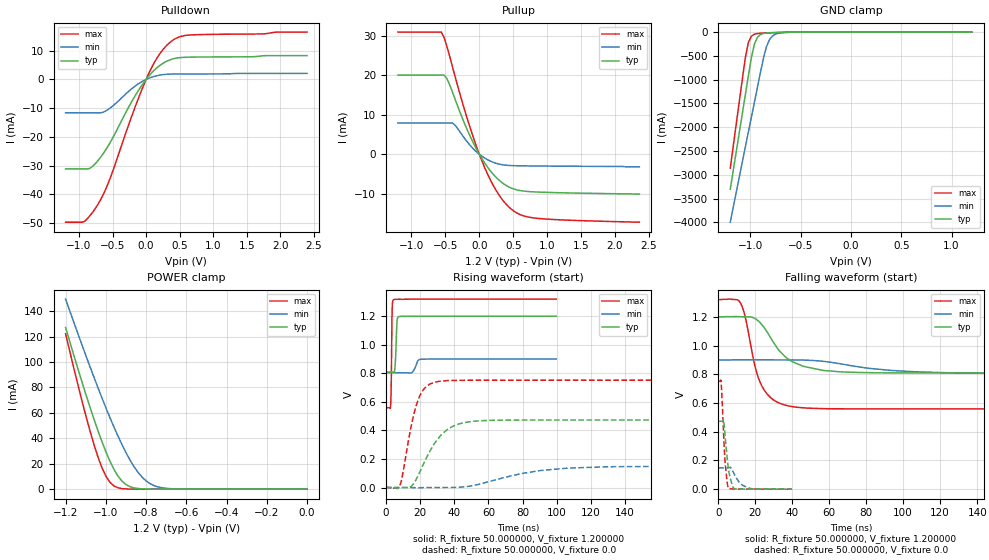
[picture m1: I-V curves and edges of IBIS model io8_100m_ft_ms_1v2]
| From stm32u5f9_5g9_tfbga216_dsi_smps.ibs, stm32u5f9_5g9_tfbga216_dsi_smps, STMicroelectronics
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|   Model io8_100m_ft_ms_1v2
[Model]  io8_100m_ft_ms_1v2
Model_type I/O
Polarity   Non-Inverting
Enable   Active-Low
Vinl =   0.360000V
Vinh =   0.840000V
Vmeas =  0.600000V
Cref =   50.000000pF
Rref =   100.000000M
Vref =   0.0V
C_comp   2.947800pF   2.877700pF   2.996100pF
[Temperature Range]   25.000000   0.140000k   -40.000000
[Pullup Reference]   1.200000V   0.900000V   1.320000V
[Pulldown Reference]   0.0V   0.0V   0.0V
[POWER Clamp Reference]   1.200000V   0.900000V   1.320000V
[GND Clamp Reference]   0.0V   0.0V   0.0V
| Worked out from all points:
|   slope of the pulldown table from 0 to 0.18 V, typ, clamps not added: 40.7 ohm
|   slope of the pullup table from 0 to 0.18 V, typ, clamps not added: 39.5 ohm
|   GND clamp passes 1 mA (typ) near -0.51 V on its own axis
|   POWER clamp passes 1 mA (typ) near -0.86 V on its own axis
|   rising waveform, R_fixture 50.000000, V_fixture 1.200000: 20-80 % time 749ps typ, 2.05ns min, 441ps max; typ from 0.809 V to 1.2 V
|   rising waveform, R_fixture 50.000000, V_fixture 0.0: 20-80 % time 14ns typ, 33.6ns min, 7.83ns max; typ from 0 V to 0.473 V
|   falling waveform, R_fixture 50.000000, V_fixture 1.200000: 20-80 % time 15.1ns typ, 36.8ns min, 8.74ns max; typ from 1.2 V to 0.809 V
|   falling waveform, R_fixture 50.000000, V_fixture 0.0: 20-80 % time 2.5ns typ, 4.76ns min, 1.84ns max; typ from 0.473 V to 0 V
[Pulldown]
|Voltage   I(typ)   I(min)   I(max)
-1.2V     -31.16mA   -11.61mA   -49.71mA
-920mV    -31.16mA   -11.61mA   -49.48mA
-840mV    -31mA      -11.61mA   -47.54mA
-720mV    -28.32mA   -11.61mA   -43.58mA
-560mV    -22.95mA   -10.37mA   -35.89mA
-200mV    -7.146mA   -2.964mA   -11.89mA
0V        0A         0A         0A
160mV     4.047mA    1.298mA    7.361mA
360mV     6.87mA     1.87mA     13mA
480mV     7.543mA    1.91mA     14.69mA
640mV     7.764mA    1.923mA    15.46mA
2.4V      8.308mA    2.101mA    16.5mA
[Pullup]
|Voltage   I(typ)   I(min)   I(max)
-1.2V     20.06mA    7.936mA    30.97mA
-560mV    20.06mA    7.936mA    30.97mA
-480mV    19.26mA    7.936mA    27.49mA
-360mV    14.08mA    7.421mA    19.88mA
-160mV    5.494mA    2.768mA    8.045mA
40mV      -1.16mA    -508.1uA   -1.774mA
240mV     -5.73mA    -2.256mA   -8.953mA
360mV     -7.518mA   -2.716mA   -11.96mA
480mV     -8.639mA   -2.877mA   -14.04mA
640mV     -9.31mA    -2.942mA   -15.55mA
880mV     -9.601mA   -2.986mA   -16.29mA
2.36V     -10.1mA    -3.2mA     -17.23mA
[GND_clamp]
|Voltage   I(typ)   I(min)   I(max)
-1.2V     -3.305A    -3.998A    -2.862A
-1.05V    -1.316A    -2.418A    -539.3mA
-1.02V    -921mA     -2.103A    -218.8mA
-990mV    -539.5mA   -1.788A    -87.43mA
-960mV    -252.1mA   -1.474A    -44.36mA
-930mV    -110.5mA   -1.16A     -30.32mA
-870mV    -28.03mA   -549.1mA   -21.09mA
-840mV    -18.43mA   -305.6mA   -18.27mA
-810mV    -13.9mA    -159.7mA   -15.73mA
-780mV    -11.23mA   -82.35mA   -13.37mA
-600mV    -2.976mA   -4.272mA   -3.058mA
1.2V      0A         14.74nA    0A
[POWER_clamp]
|Voltage   I(typ)   I(min)   I(max)
-1.2V     127mA      149.4mA    122.2mA
-1.12V    84.97mA    114mA      70.27mA
-1.06V    55.51mA    88.42mA    35.67mA
-1.02V    37.63mA    72.04mA    17.17mA
-1V       29.51mA    64.13mA    10.3mA
-960mV    15.69mA    48.99mA    2.571mA
-900mV    3.624mA    28.77mA    182.8uA
-840mV    490.7uA    13.24mA    11.35uA
-800mV    116.8uA    6.532mA    1.77uA
-740mV    13.2uA     1.723mA    109.1nA
-620mV    167.3nA    79.35uA    0A
0V        0A         17.84nA    0A
[Ramp]
| variable   typ   min   max
dV/dt_r  0.28373/13.95894n   88.89587m/33.56367n 0.45095/7.81701n
dV/dt_f  0.23464/15.11036n   57.88200m/36.76440n 0.45667/8.72831n
R_load = 50.000000
[Rising Waveform]
R_fixture= 50.000000
V_fixture= 1.200000
V_fixture_min= 0.900000
V_fixture_max= 1.320000
|time   V(typ)   V(min)   V(max)
0s        809mV      803.5mV    558.9mV
2.803ns   809mV      803.5mV    575.1mV
3.203ns   809.1mV    803.5mV    763.8mV
3.604ns   809mV      803.5mV    1.211V
4.605ns   804.7mV    803.5mV    1.316V
5.405ns   852.1mV    803.5mV    1.318V
6.607ns   1.173V     803.5mV    1.318V
7.608ns   1.197V     803.5mV    1.319V
20.62ns   1.199V     898.4mV    1.32V
99.7ns    1.2V       900mV      1.32V
[Rising Waveform]
R_fixture= 50.000000
V_fixture= 0.0
V_fixture_min= 0.0
V_fixture_max= 0.0
|time   V(typ)   V(min)   V(max)
0s        2.143uV    1.134uV    2.528uV
7.808ns   -1.504mV   305.6nV    5.314mV
14.41ns   4.444mV    -158.6uV   405.8mV
18.62ns   77.49mV    -1.841mV   605.4mV
23.42ns   199.9mV    -199.4uV   704.4mV
30.63ns   342.8mV    -16.77uV   742.6mV
39.64ns   431.6mV    522.9uV    750.2mV
57.66ns   468.9mV    32.7mV     751.5mV
106.9ns   472.8mV    136.2mV    751.6mV
299.1ns   472.9mV    148.2mV    751.6mV
[Falling Waveform]
R_fixture= 50.000000
V_fixture= 1.200000
V_fixture_min= 0.900000
V_fixture_max= 1.320000
|time   V(typ)   V(min)   V(max)
0s        1.2V       900mV      1.32V
12.01ns   1.201V     900.6mV    1.297V
14.41ns   1.2V       900.5mV    1.21V
20.02ns   1.187V     900.5mV    849.1mV
23.22ns   1.151V     900.5mV    727.8mV
30.43ns   1.011V     900.2mV    617mV
40.84ns   883.5mV    899.9mV    573.3mV
65.67ns   817.3mV    873.9mV    559.6mV
123.3ns   809mV      810.9mV    558.9mV
398.8ns   809mV      803.5mV    558.9mV
[Falling Waveform]
R_fixture= 50.000000
V_fixture= 0.0
V_fixture_min= 0.0
V_fixture_max= 0.0
|time   V(typ)   V(min)   V(max)
0s        472.9mV    148.2mV    751.6mV
1.522ns   472.9mV    148.2mV    755.6mV
2.883ns   479mV      148.3mV    395.5mV
3.604ns   393.1mV    148.3mV    211.8mV
4.645ns   246.5mV    148.1mV    71.2mV
5.445ns   150.6mV    148.4mV    9.118mV
7.367ns   36.29mV    138.3mV    1.711mV
8.729ns   2.867mV    103.8mV    1.121mV
16.5ns    365.8uV    8.357mV    337.1uV
39.88ns   2.143uV    1.134uV    2.528uV
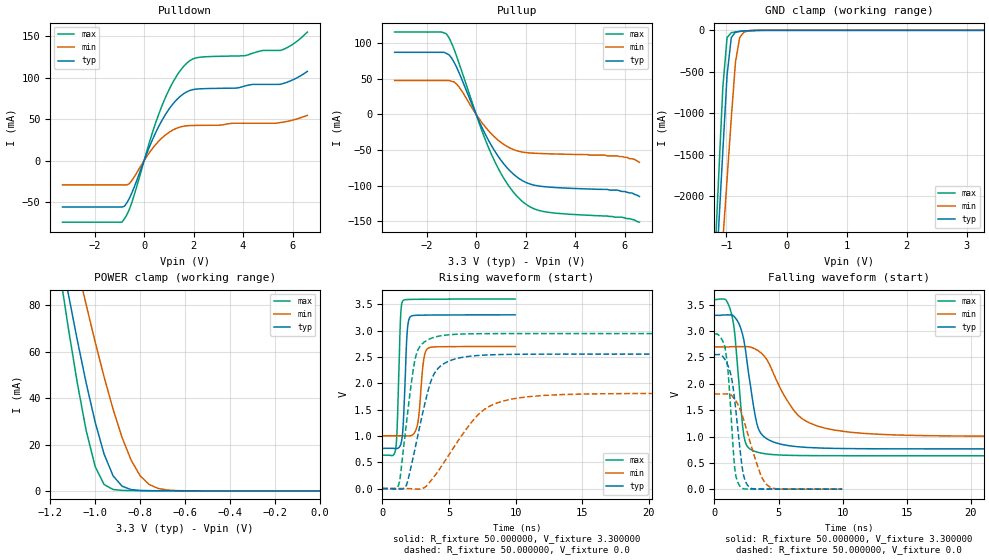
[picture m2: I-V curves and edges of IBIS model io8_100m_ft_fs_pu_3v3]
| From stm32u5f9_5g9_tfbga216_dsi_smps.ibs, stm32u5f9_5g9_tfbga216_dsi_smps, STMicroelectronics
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|   Model io8_100m_ft_fs_pu_3v3
[Model]  io8_100m_ft_fs_pu_3v3
Model_type I/O
Polarity   Non-Inverting
Enable   Active-Low
Vinl =   0.990000V
Vinh =   2.310000V
Vmeas =  1.650000V
Cref =   50.000000pF
Rref =   100.000000M
Vref =   0.0V
C_comp   3.313100pF   3.281800pF   3.354500pF
[Temperature Range]   25.000000   0.140000k   -40.000000
[Pullup Reference]   3.300000V   2.700000V   3.600000V
[Pulldown Reference]   0.0V   0.0V   0.0V
[POWER Clamp Reference]   3.300000V   2.700000V   3.600000V
[GND Clamp Reference]   0.0V   0.0V   0.0V
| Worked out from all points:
|   slope of the pulldown table from 0 to 0.495 V, typ, clamps not added: 14 ohm
|   slope of the pullup table from 0 to 0.495 V, typ, clamps not added: 13.7 ohm
|   GND clamp passes 1 mA (typ) near -0.51 V on its own axis
|   POWER clamp passes 1 mA (typ) near -0.85 V on its own axis
|   rising waveform, R_fixture 50.000000, V_fixture 3.300000: 20-80 % time 244ps typ, 341ps min, 207ps max; typ from 0.765 V to 3.3 V
|   rising waveform, R_fixture 50.000000, V_fixture 0.0: 20-80 % time 1.41ns typ, 3.11ns min, 872ps max; typ from 0.001 V to 2.55 V
|   falling waveform, R_fixture 50.000000, V_fixture 3.300000: 20-80 % time 962ps typ, 2.52ns min, 631ps max; typ from 3.3 V to 0.765 V
|   falling waveform, R_fixture 50.000000, V_fixture 0.0: 20-80 % time 726ps typ, 1.36ns min, 504ps max; typ from 2.55 V to 0.001 V
[Pulldown]
|Voltage   I(typ)   I(min)   I(max)
-3.3V     -56.06mA   -29.42mA   -74.35mA
-900mV    -56.06mA   -29.42mA   -74.35mA
-700mV    -51.09mA   -29.42mA   -65.48mA
-500mV    -39.32mA   -24.2mA    -50.88mA
300mV     22.62mA    13.13mA    30.42mA
800mV     52.54mA    29.36mA    71.75mA
1.3V      72.91mA    38.82mA    101.4mA
1.8V      84.02mA    42.13mA    119.4mA
2.3V      86.61mA    42.5mA     124.8mA
5.5V      91.97mA    45.76mA    132.8mA
6V        97.2mA     48.8mA     140mA
6.6V      107.6mA    54.5mA     155mA
[Pullup]
|Voltage   I(typ)   I(min)   I(max)
-3.3V     87.15mA    47.7mA     115.5mA
-1.2V     85.45mA    47.7mA     112.8mA
-1V       79.36mA    46.62mA    100.4mA
-700mV    59.07mA    38.77mA    72.39mA
200mV     -15.65mA   -9.933mA   -19.95mA
700mV     -48.51mA   -30.11mA   -62.22mA
1.3V      -76.68mA   -45.83mA   -99.4mA
1.9V      -93.37mA   -52.9mA    -122.9mA
2.3V      -98.71mA   -54.23mA   -131.6mA
2.8V      -101.3mA   -54.97mA   -136.5mA
5.7V      -106mA     -58mA      -144mA
6.6V      -115mA     -67mA      -151mA
[GND_clamp]
|Voltage   I(typ)   I(min)   I(max)
-3.3V     -9.848A    -9.957A    -9.458A
-1.2V     -3.312A    -4.013A    -2.863A
-1.13V    -2.381A    -3.274A    -1.769A
-1.06V    -1.452A    -2.535A    -684.7mA
-990mV    -542.9mA   -1.798A    -88.02mA
-920mV    -87.11mA   -1.064A    -28.44mA
-850mV    -22.1mA    -382.4mA   -19.61mA
-780mV    -11.97mA   -86.98mA   -13.71mA
-710mV    -7.619mA   -22.26mA   -8.745mA
-640mV    -4.493mA   -7.773mA   -4.817mA
-360mV    -31.22uA   -172.6uA   -8.607uA
3.28V     0A         15.66nA    -5.841nA
[POWER_clamp]
|Voltage   I(typ)   I(min)   I(max)
-3.28V    1.355A     1.167A     1.665A
-1.16V    105.8mA    131.6mA    95.87mA
-1.12V    85.08mA    114mA      70.45mA
-1.08V    65.19mA    96.88mA    46.75mA
-1.04V    46.48mA    80.2mA     25.96mA
-1V       29.64mA    64.18mA    10.49mA
-960mV    15.81mA    49.06mA    2.743mA
-920mV    6.481mA    35.16mA    612.9uA
-840mV    578.2uA    13.29mA    138.5uA
-760mV    94.37uA    2.807mA    98.56uA
-640mV    40.55uA    159.2uA    59.96uA
0V        0A         19.29nA    0A
[Ramp]
| variable   typ   min   max
dV/dt_r  1.53214/1.41049n   1.08405/3.10150n   1.76624/0.87017n
dV/dt_f  1.52095/0.95861n   1.01838/2.51496n   1.77908/0.62510n
R_load = 50.000000
[Rising Waveform]
R_fixture= 50.000000
V_fixture= 3.300000
V_fixture_min= 2.700000
V_fixture_max= 3.600000
|time   V(typ)   V(min)   V(max)
0s        765.1mV    1.003V     634.9mV
1.021ns   760.9mV    1.003V     795.6mV
1.361ns   828mV      1.003V     3.225V
1.542ns   1.123V     1.002V     3.567V
1.842ns   2.89V      1V         3.591V
2.102ns   3.266V     1.003V     3.593V
2.663ns   3.293V     1.25V      3.596V
3.063ns   3.295V     2.372V     3.597V
3.363ns   3.296V     2.653V     3.597V
9.97ns    3.3V       2.7V       3.6V
[Rising Waveform]
R_fixture= 50.000000
V_fixture= 0.0
V_fixture_min= 0.0
V_fixture_max= 0.0
|time   V(typ)   V(min)   V(max)
0s        834.3uV    854uV      878uV
1.201ns   -6.187mV   859.8uV    56.02mV
1.802ns   61.56mV    847.4uV    1.231V
2.302ns   584mV      -5.222mV   2.233V
2.603ns   935mV      -9.197mV   2.593V
3.504ns   1.924V     106.7mV    2.838V
4.104ns   2.26V      303mV      2.888V
7.307ns   2.531V     1.431V     2.942V
10.41ns   2.551V     1.728V     2.944V
49.85ns   2.554V     1.808V     2.944V
[Falling Waveform]
R_fixture= 50.000000
V_fixture= 3.300000
V_fixture_min= 2.700000
V_fixture_max= 3.600000
|time   V(typ)   V(min)   V(max)
0s        3.3V       2.7V       3.6V
1.301ns   3.307V     2.704V     3.356V
1.602ns   3.26V      2.706V     2.918V
2.002ns   3.088V     2.706V     1.742V
2.402ns   2.676V     2.706V     899.2mV
3.103ns   1.5V       2.67V      723.1mV
3.504ns   1.109V     2.614V     693.6mV
6.507ns   806.1mV    1.409V     640mV
9.51ns    774.3mV    1.117V     635.7mV
49.85ns   765.1mV    1.003V     634.9mV
[Falling Waveform]
R_fixture= 50.000000
V_fixture= 0.0
V_fixture_min= 0.0
V_fixture_max= 0.0
|time   V(typ)   V(min)   V(max)
0s        2.554V     1.808V     2.944V
860.9ps   2.444V     1.808V     2.631V
1.101ns   2.316V     1.811V     2.114V
1.582ns   1.687V     1.707V     407.7mV
2.022ns   699.6mV    1.505V     47.01mV
2.282ns   258.1mV    1.317V     8.261mV
2.583ns   76.46mV    1.065V     3.648mV
3.564ns   3.141mV    304.1mV    2.036mV
4.204ns   2.271mV    61.7mV     1.751mV
9.97ns    834.3uV    854uV      878uV
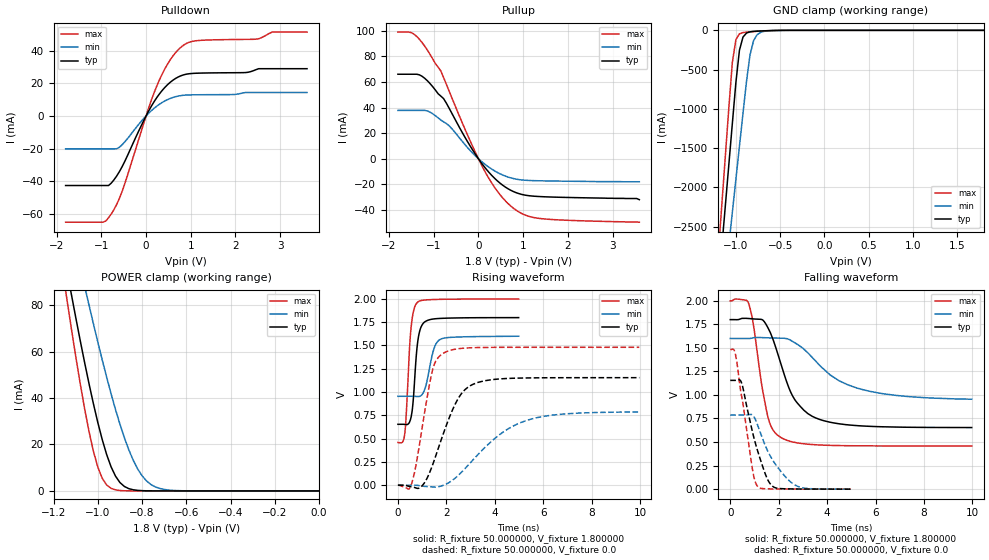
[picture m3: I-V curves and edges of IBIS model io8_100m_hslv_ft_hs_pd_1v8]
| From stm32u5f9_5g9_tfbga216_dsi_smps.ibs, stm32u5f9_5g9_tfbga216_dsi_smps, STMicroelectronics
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|   Model io8_100m_hslv_ft_hs_pd_1v8
[Model]  io8_100m_hslv_ft_hs_pd_1v8
Model_type I/O
Polarity   Non-Inverting
Enable   Active-Low
Vinl =   0.540000V
Vinh =   1.260000V
Vmeas =  0.900000V
Cref =   50.000000pF
Rref =   100.000000M
Vref =   0.0V
C_comp   3.235100pF   3.233200pF   3.282800pF
[Temperature Range]   25.000000   0.140000k   -40.000000
[Pullup Reference]   1.800000V   1.600000V   2.000000V
[Pulldown Reference]   0.0V   0.0V   0.0V
[POWER Clamp Reference]   1.800000V   1.600000V   2.000000V
[GND Clamp Reference]   0.0V   0.0V   0.0V
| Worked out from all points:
|   slope of the pulldown table from 0 to 0.27 V, typ, clamps not added: 21.7 ohm
|   slope of the pullup table from 0 to 0.27 V, typ, clamps not added: 22.6 ohm
|   GND clamp passes 1 mA (typ) near -0.51 V on its own axis
|   POWER clamp passes 1 mA (typ) near -0.86 V on its own axis
|   rising waveform, R_fixture 50.000000, V_fixture 1.800000: 20-80 % time 212ps typ, 327ps min, 198ps max; typ from 0.654 V to 1.8 V
|   rising waveform, R_fixture 50.000000, V_fixture 0.0: 20-80 % time 1.02ns typ, 2.02ns min, 582ps max; typ from 0 V to 1.15 V
|   falling waveform, R_fixture 50.000000, V_fixture 1.800000: 20-80 % time 1.08ns typ, 2.01ns min, 567ps max; typ from 1.8 V to 0.654 V
|   falling waveform, R_fixture 50.000000, V_fixture 0.0: 20-80 % time 708ps typ, 988ps min, 509ps max; typ from 1.15 V to 0 V
[Pulldown]
|Voltage   I(typ)   I(min)   I(max)
-1.8V     -42.74mA   -20.21mA   -65.25mA
-960mV    -42.74mA   -20.21mA   -65.25mA
-780mV    -41.3mA    -20.21mA   -60.25mA
-540mV    -31.39mA   -17.82mA   -46.65mA
0V        0A         -500fA     0A
240mV     11.28mA    6.002mA    18.38mA
480mV     19.17mA    10.02mA    31.83mA
780mV     24.67mA    12.5mA     42.21mA
1.14V     26.24mA    12.99mA    46.23mA
2.46V     28.42mA    14.39mA    47.14mA
2.82V     29mA       14.39mA    51.49mA
3.6V      29mA       14.39mA    51.49mA
[Pullup]
|Voltage   I(typ)   I(min)   I(max)
-1.8V     66.02mA    37.77mA    98.95mA
-1.44V    66.02mA    37.77mA    97.33mA
-1.14V    60.88mA    37.29mA    84.79mA
-840mV    48.93mA    30.23mA    68.56mA
-660mV    39.81mA    25.95mA    53.26mA
-300mV    16.72mA    11mA       23.08mA
120mV     -5.748mA   -3.603mA   -8.317mA
420mV     -17.18mA   -10.64mA   -25.23mA
780mV     -25.61mA   -15.48mA   -38.6mA
1.08V     -28.66mA   -16.9mA    -44.47mA
1.38V     -29.58mA   -17.26mA   -46.72mA
3.6V      -32mA      -18mA      -49.6mA
[GND_clamp]
|Voltage   I(typ)   I(min)   I(max)
-1.8V     -9.707A    -9.942A    -9.774A
-1.2V     -3.309A    -4.006A    -2.865A
-1.16V    -2.777A    -3.584A    -2.239A
-1.12V    -2.246A    -3.162A    -1.614A
-1.04V    -1.186A    -2.319A    -408.7mA
-1V       -663.9mA   -1.898A    -117.8mA
-960mV    -254mA     -1.478A    -45.15mA
-920mV    -86.04mA   -1.06A     -28.6mA
-840mV    -19.13mA   -308.9mA   -18.75mA
-800mV    -13.4mA    -130.8mA   -15.33mA
-720mV    -7.959mA   -25.38mA   -9.395mA
1.8V      45.71uA    33.33uA    56.11uA
[POWER_clamp]
|Voltage   I(typ)   I(min)   I(max)
-1.8V     470.8mA    433.7mA    554.6mA
-1.14V    95.25mA    122.7mA    82.82mA
-1.12V    84.97mA    114mA      70.27mA
-1.06V    55.51mA    88.42mA    35.67mA
-1.04V    46.34mA    80.15mA    25.76mA
-1V       29.51mA    64.13mA    10.3mA
-940mV    10.39mA    41.86mA    1.109mA
-900mV    3.624mA    28.77mA    182.8uA
-840mV    490.7uA    13.24mA    11.35uA
-800mV    116.8uA    6.532mA    1.77uA
-740mV    13.2uA     1.723mA    109.2nA
0V        0A         18.72nA    0A
[Ramp]
| variable   typ   min   max
dV/dt_r  0.69258/1.02276n   0.47011/2.01839n   0.88824/0.58102n
dV/dt_f  0.68713/1.08343n   0.37954/1.99476n   0.92451/0.56651n
R_load = 50.000000
[Rising Waveform]
R_fixture= 50.000000
V_fixture= 1.800000
V_fixture_min= 1.600000
V_fixture_max= 2.000000
|time   V(typ)   V(min)   V(max)
0s        653.8mV    954.5mV    458.7mV
200.2ps   654mV      954.6mV    467.1mV
290.3ps   652.3mV    954.7mV    571.9mV
520.5ps   707.2mV    955mV      1.627V
620.6ps   879mV      955mV      1.839V
780.8ps   1.456V     952.3mV    1.957V
1.031ns   1.733V     986.6mV    1.986V
1.481ns   1.785V     1.46V      1.994V
1.752ns   1.791V     1.566V     1.996V
4.985ns   1.799V     1.599V     1.998V
[Rising Waveform]
R_fixture= 50.000000
V_fixture= 0.0
V_fixture_min= 0.0
V_fixture_max= 0.0
|time   V(typ)   V(min)   V(max)
0s        -109.8uV   -29.99uV   3.004uV
560.6ps   -17.99mV   -33.32uV   13.46mV
1.001ns   -5.882mV   -9.778mV   619.1mV
1.421ns   210.7mV    -18.62mV   1.229V
1.882ns   558mV      -215.9uV   1.418V
2.563ns   960.9mV    122.9mV    1.467V
3.303ns   1.103V     328.5mV    1.478V
4.525ns   1.146V     600.6mV    1.48V
5.646ns   1.153V     719.7mV    1.481V
9.97ns    1.155V     786.3mV    1.481V
[Falling Waveform]
R_fixture= 50.000000
V_fixture= 1.800000
V_fixture_min= 1.600000
V_fixture_max= 2.000000
|time   V(typ)   V(min)   V(max)
0s        1.799V     1.599V     1.998V
740.7ps   1.811V     1.599V     1.983V
920.9ps   1.807V     1.605V     1.8V
1.301ns   1.8V       1.609V     1.103V
1.542ns   1.72V      1.606V     781.7mV
2.082ns   1.337V     1.602V     549.5mV
2.683ns   943.2mV    1.551V     495.1mV
3.704ns   738.9mV    1.311V     468.6mV
5.766ns   666.7mV    1.038V     459.6mV
9.97ns    653.8mV    954.5mV    458.7mV
[Falling Waveform]
R_fixture= 50.000000
V_fixture= 0.0
V_fixture_min= 0.0
V_fixture_max= 0.0
|time   V(typ)   V(min)   V(max)
0s        1.155V     786.3mV    1.481V
140.1ps   1.155V     786.3mV    1.482V
210.2ps   1.155V     786.3mV    1.433V
450.5ps   1.139V     786.4mV    1.011V
940.9ps   582.1mV    780.6mV    173.9mV
1.141ns   396.9mV    672.3mV    25.37mV
1.481ns   138.3mV    441.5mV    4.151mV
1.682ns   46.51mV    338.4mV    2.881mV
2.643ns   2.19mV     48.76mV    770.1uV
4.985ns   -109.8uV   -29.99uV   3.004uV
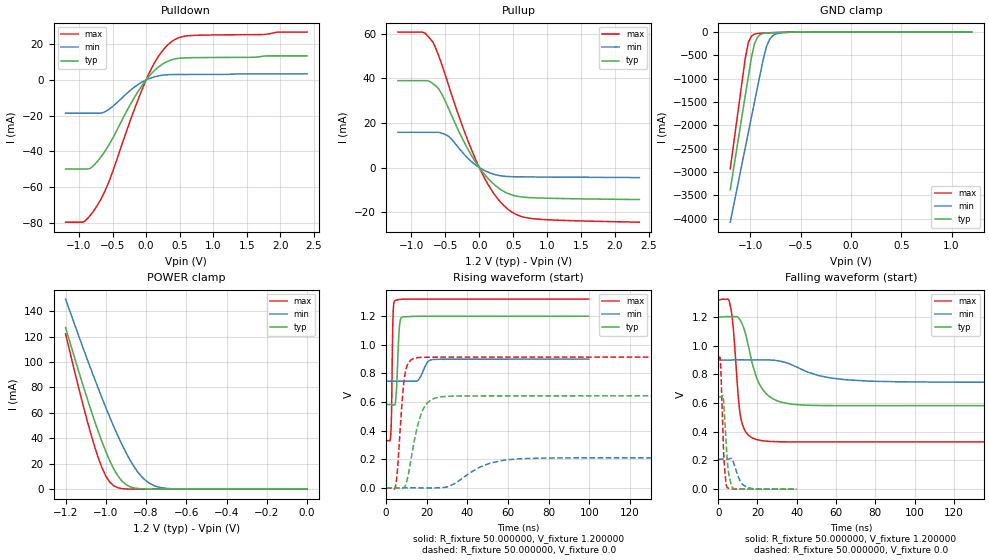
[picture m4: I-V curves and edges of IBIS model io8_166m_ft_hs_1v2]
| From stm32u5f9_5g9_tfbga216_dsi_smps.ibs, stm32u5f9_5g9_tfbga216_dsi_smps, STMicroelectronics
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|   Model io8_166m_ft_hs_1v2
[Model]  io8_166m_ft_hs_1v2
Model_type I/O
Polarity   Non-Inverting
Enable   Active-Low
Vinl =   0.360000V
Vinh =   0.840000V
Vmeas =  0.600000V
Cref =   50.000000pF
Rref =   100.000000M
Vref =   0.0V
C_comp   3.151500pF   3.086800pF   3.197700pF
[Temperature Range]   25.000000   0.140000k   -40.000000
[Pullup Reference]   1.200000V   0.900000V   1.320000V
[Pulldown Reference]   0.0V   0.0V   0.0V
[POWER Clamp Reference]   1.200000V   0.900000V   1.320000V
[GND Clamp Reference]   0.0V   0.0V   0.0V
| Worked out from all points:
|   slope of the pulldown table from 0 to 0.18 V, typ, clamps not added: 25.4 ohm
|   slope of the pullup table from 0 to 0.18 V, typ, clamps not added: 27.8 ohm
|   GND clamp passes 1 mA (typ) near -0.51 V on its own axis
|   POWER clamp passes 1 mA (typ) near -0.86 V on its own axis
|   rising waveform, R_fixture 50.000000, V_fixture 1.200000: 20-80 % time 1.12ns typ, 3.03ns min, 582ps max; typ from 0.582 V to 1.2 V
|   rising waveform, R_fixture 50.000000, V_fixture 0.0: 20-80 % time 5.8ns typ, 15.1ns min, 2.79ns max; typ from 0 V to 0.643 V
|   falling waveform, R_fixture 50.000000, V_fixture 1.200000: 20-80 % time 8.14ns typ, 19.6ns min, 3.49ns max; typ from 1.2 V to 0.582 V
|   falling waveform, R_fixture 50.000000, V_fixture 0.0: 20-80 % time 1.93ns typ, 3.6ns min, 1.46ns max; typ from 0.643 V to 0 V
[Pulldown]
|Voltage   I(typ)   I(min)   I(max)
-1.2V     -49.86mA   -18.57mA   -79.57mA
-920mV    -49.86mA   -18.57mA   -79.2mA
-840mV    -49.6mA    -18.57mA   -76.08mA
-720mV    -45.32mA   -18.57mA   -69.74mA
-560mV    -36.71mA   -16.58mA   -57.44mA
-200mV    -11.43mA   -4.74mA    -19.03mA
0V        0A         -500fA     0A
160mV     6.477mA    2.075mA    11.78mA
360mV     10.99mA    2.99mA     20.81mA
480mV     12.07mA    3.054mA    23.53mA
640mV     12.43mA    3.075mA    24.76mA
2.4V      13.46mA    3.37mA     26.78mA
[Pullup]
|Voltage   I(typ)   I(min)   I(max)
-1.2V     38.95mA    15.81mA    60.71mA
-840mV    38.95mA    15.81mA    60.71mA
-680mV    37.51mA    15.81mA    56.01mA
-600mV    35.31mA    15.81mA    50.19mA
-440mV    25.54mA    13.66mA    35.67mA
-240mV    12.39mA    6.512mA    17.85mA
-40mV     1.772mA    818.2uA    2.67mA
200mV     -7.072mA   -2.852mA   -11mA
440mV     -11.84mA   -4.03mA    -19.1mA
600mV     -13.07mA   -4.154mA   -21.71mA
840mV     -13.59mA   -4.223mA   -23.04mA
2.36V     -14.3mA    -4.5mA     -24.47mA
[GND_clamp]
|Voltage   I(typ)   I(min)   I(max)
-1.2V     -3.379A    -4.076A    -2.932A
-1.05V    -1.35A     -2.47A     -550.7mA
-1.02V    -947.8mA   -2.149A    -221.5mA
-990mV    -552.4mA   -1.829A    -88.44mA
-960mV    -255.3mA   -1.51A     -44.87mA
-930mV    -111.8mA   -1.191A    -30.68mA
-870mV    -28.36mA   -564.6mA   -21.34mA
-840mV    -18.65mA   -309.5mA   -18.49mA
-810mV    -14.07mA   -161.6mA   -15.92mA
-780mV    -11.37mA   -83.33mA   -13.53mA
-600mV    -3.009mA   -4.322mA   -3.091mA
1.2V      0A         13.65nA    0A
[POWER_clamp]
|Voltage   I(typ)   I(min)   I(max)
-1.2V     127mA      149.4mA    122.2mA
-1.12V    84.97mA    114mA      70.27mA
-1.06V    55.51mA    88.42mA    35.67mA
-1.02V    37.63mA    72.04mA    17.17mA
-1V       29.51mA    64.13mA    10.3mA
-960mV    15.69mA    48.99mA    2.571mA
-900mV    3.624mA    28.77mA    182.8uA
-840mV    490.7uA    13.24mA    11.35uA
-800mV    116.8uA    6.532mA    1.77uA
-740mV    13.2uA     1.724mA    109.1nA
-620mV    167.4nA    79.36uA    0A
0V        0A         17.87nA    0A
[Ramp]
| variable   typ   min   max
dV/dt_r  0.38563/5.78961n   0.12553/15.13591n   0.54825/2.78155n
dV/dt_f  0.37087/8.12844n   92.46600m/19.53427n 0.59438/3.47576n
R_load = 50.000000
[Rising Waveform]
R_fixture= 50.000000
V_fixture= 1.200000
V_fixture_min= 0.900000
V_fixture_max= 1.320000
|time   V(typ)   V(min)   V(max)
0s        581.9mV    745.9mV    329.4mV
2.402ns   582mV      745.9mV    368.4mV
2.803ns   582mV      745.9mV    528.7mV
3.203ns   581.6mV    745.9mV    975.3mV
3.604ns   580.4mV    745.9mV    1.234V
4.605ns   589.2mV    745.9mV    1.31V
6.607ns   1.116V     745.9mV    1.317V
8.008ns   1.194V     745.9mV    1.319V
23.02ns   1.2V       897.1mV    1.32V
99.7ns    1.2V       900mV      1.32V
[Rising Waveform]
R_fixture= 50.000000
V_fixture= 0.0
V_fixture_min= 0.0
V_fixture_max= 0.0
|time   V(typ)   V(min)   V(max)
0s        1.414uV    1.127uV    1.262uV
4.805ns   -1.543mV   775nV      12.85mV
9.209ns   6.521mV    -355.1nV   778.5mV
11.21ns   105.2mV    6.31uV     875.7mV
14.01ns   330.4mV    38.89uV    905.4mV
19.22ns   571.2mV    -1.424mV   912.9mV
28.03ns   637.4mV    1.434mV    913.7mV
51.25ns   642.6mV    172.4mV    913.7mV
65.27ns   642.7mV    202.5mV    913.7mV
199.4ns   642.8mV    209.3mV    913.8mV
[Falling Waveform]
R_fixture= 50.000000
V_fixture= 1.200000
V_fixture_min= 0.900000
V_fixture_max= 1.320000
|time   V(typ)   V(min)   V(max)
0s        1.2V       900mV      1.32V
5.606ns   1.202V     899.9mV    1.313V
7.207ns   1.202V     900.3mV    1.187V
10.41ns   1.194V     901.2mV    615.4mV
11.61ns   1.168V     901.2mV    491.2mV
19.22ns   791.3mV    900.8mV    347.1mV
25.63ns   650.8mV    900.3mV    333.2mV
37.64ns   592.2mV    865.2mV    329.6mV
76.48ns   581.9mV    753.3mV    329.4mV
199.4ns   581.9mV    745.9mV    329.4mV
[Falling Waveform]
R_fixture= 50.000000
V_fixture= 0.0
V_fixture_min= 0.0
V_fixture_max= 0.0
|time   V(typ)   V(min)   V(max)
0s        642.8mV    209.3mV    913.8mV
1.201ns   642.6mV    209.3mV    875.6mV
2.563ns   642.5mV    209.3mV    328.4mV
3.443ns   463.9mV    209.2mV    119mV
4.484ns   231.6mV    209mV      12.76mV
5.445ns   101.8mV    210.7mV    5.439mV
7.688ns   5.682mV    190.9mV    1.367mV
11.61ns   1.272mV    46.46mV    370.5uV
15.38ns   600.5uV    10.87mV    143.5uV
39.88ns   1.414uV    1.127uV    1.262uV
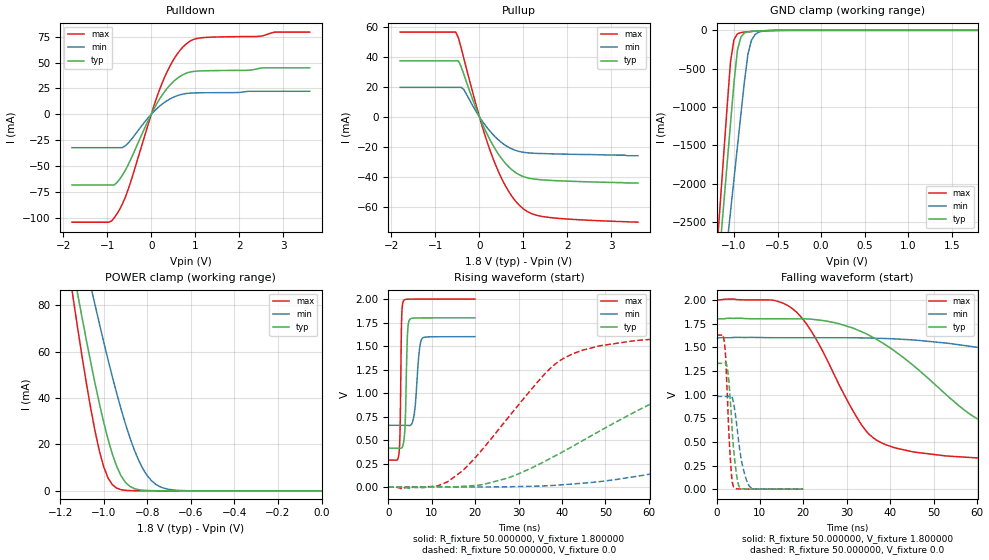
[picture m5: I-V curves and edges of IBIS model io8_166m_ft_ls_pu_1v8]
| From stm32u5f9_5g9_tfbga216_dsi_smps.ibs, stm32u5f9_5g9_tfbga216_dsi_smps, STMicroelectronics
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|   Model io8_166m_ft_ls_pu_1v8
[Model]  io8_166m_ft_ls_pu_1v8
Model_type I/O
Polarity   Non-Inverting
Enable   Active-Low
Vinl =   0.540000V
Vinh =   1.260000V
Vmeas =  0.900000V
Cref =   50.000000pF
Rref =   100.000000M
Vref =   0.0V
C_comp   3.358100pF   3.352600pF   3.400200pF
[Temperature Range]   25.000000   0.140000k   -40.000000
[Pullup Reference]   1.800000V   1.600000V   2.000000V
[Pulldown Reference]   0.0V   0.0V   0.0V
[POWER Clamp Reference]   1.800000V   1.600000V   2.000000V
[GND Clamp Reference]   0.0V   0.0V   0.0V
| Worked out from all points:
|   slope of the pulldown table from 0 to 0.27 V, typ, clamps not added: 13.6 ohm
|   slope of the pullup table from 0 to 0.27 V, typ, clamps not added: 15.9 ohm
|   GND clamp passes 1 mA (typ) near -0.51 V on its own axis
|   POWER clamp passes 1 mA (typ) near -0.86 V on its own axis
|   rising waveform, R_fixture 50.000000, V_fixture 1.800000: 20-80 % time 442ps typ, 900ps min, 292ps max; typ from 0.414 V to 1.8 V
|   rising waveform, R_fixture 50.000000, V_fixture 0.0: 20-80 % time 34.1ns typ, 74.8ns min, 18ns max; typ from 0 V to 1.33 V
|   falling waveform, R_fixture 50.000000, V_fixture 1.800000: 20-80 % time 23.4ns typ, 59.3ns min, 12.2ns max; typ from 1.8 V to 0.414 V
|   falling waveform, R_fixture 50.000000, V_fixture 0.0: 20-80 % time 1.32ns typ, 1.9ns min, 976ps max; typ from 1.33 V to 0 V
[Pulldown]
|Voltage   I(typ)   I(min)   I(max)
-1.8V     -68.38mA   -32.32mA   -104.4mA
-960mV    -68.38mA   -32.32mA   -104.4mA
-780mV    -66.08mA   -32.32mA   -96.43mA
-660mV    -59.2mA    -32.31mA   -87.22mA
-540mV    -50.22mA   -28.51mA   -74.66mA
0V        0A         0A         0A
240mV     18.04mA    9.6mA      29.42mA
480mV     30.68mA    16.02mA    50.95mA
780mV     39.48mA    19.99mA    67.56mA
1.14V     41.99mA    20.78mA    74.01mA
2.82V     44.92mA    22.27mA    79.53mA
3.6V      44.92mA    22.27mA    79.53mA
[Pullup]
|Voltage   I(typ)   I(min)   I(max)
-1.8V     37.48mA    19.76mA    56.75mA
-540mV    37.48mA    19.76mA    56.75mA
-480mV    37.48mA    19.76mA    53.06mA
-360mV    28.94mA    18.48mA    39.74mA
0V        630fA      250pA      10fA
300mV     -18.63mA   -11.6mA    -27.18mA
600mV     -31.41mA   -19.24mA   -46.67mA
780mV     -36.41mA   -22mA      -54.88mA
960mV     -39.54mA   -23.52mA   -60.64mA
1.2V      -41.44mA   -24.28mA   -64.93mA
1.56V     -42.42mA   -24.69mA   -67.24mA
3.6V      -44.3mA    -26mA      -70.5mA
[GND_clamp]
|Voltage   I(typ)   I(min)   I(max)
-1.8V     -9.908A    -9.683A    -9.994A
-1.2V     -3.383A    -4.084A    -2.934A
-1.16V    -2.841A    -3.655A    -2.294A
-1.12V    -2.299A    -3.226A    -1.656A
-1.04V    -1.218A    -2.369A    -414.2mA
-1V       -684.7mA   -1.941A    -119.2mA
-960mV    -257.2mA   -1.514A    -45.66mA
-920mV    -87.03mA   -1.089A    -28.93mA
-840mV    -19.35mA   -312.8mA   -18.97mA
-800mV    -13.55mA   -132.4mA   -15.49mA
-720mV    -8.042mA   -25.67mA   -9.491mA
1.8V      0A         13.64nA    0A
[POWER_clamp]
|Voltage   I(typ)   I(min)   I(max)
-1.8V     470.9mA    433.7mA    554.6mA
-1.14V    95.28mA    122.7mA    82.88mA
-1.12V    85mA       114mA      70.34mA
-1.06V    55.55mA    88.43mA    35.73mA
-1.04V    46.38mA    80.17mA    25.83mA
-1V       29.54mA    64.14mA    10.37mA
-940mV    10.43mA    41.88mA    1.177mA
-900mV    3.66mA     28.79mA    250.5uA
-840mV    527.2uA    13.26mA    95.95uA
-800mV    154uA      6.55mA     88.4uA
-740mV    59.84uA    1.741mA    70.38uA
0V        0A         18.18nA    0A
[Ramp]
| variable   typ   min   max
dV/dt_r  0.79757/34.08917n   0.58751/74.68112n   0.97651/17.99188n
dV/dt_f  0.83133/23.35069n   0.56457/59.24573n   1.02743/12.17504n
R_load = 50.000000
[Rising Waveform]
R_fixture= 50.000000
V_fixture= 1.800000
V_fixture_min= 1.600000
V_fixture_max= 2.000000
|time   V(typ)   V(min)   V(max)
0s        414.4mV    657.5mV    287.6mV
2.482ns   414.1mV    657.5mV    373mV
2.723ns   413.2mV    657.5mV    662.3mV
3.043ns   415.2mV    657.5mV    1.754V
3.483ns   471.3mV    657.5mV    1.98V
3.924ns   739.9mV    657.3mV    1.996V
4.404ns   1.616V     656.3mV    1.998V
4.885ns   1.78V      655mV      1.999V
7.728ns   1.8V       1.578V     2V
19.94ns   1.8V       1.6V       2V
[Rising Waveform]
R_fixture= 50.000000
V_fixture= 0.0
V_fixture_min= 0.0
V_fixture_max= 0.0
|time   V(typ)   V(min)   V(max)
0s        425uV      507.6uV    388.2uV
13.61ns   2.045mV    1.498mV    55.73mV
27.23ns   92.97mV    3.236mV    718mV
38.44ns   332.5mV    19.38mV    1.309V
56.86ns   800.8mV    112mV      1.558V
72.07ns   1.098V     238.7mV    1.601V
88.89ns   1.225V     392.8mV    1.619V
133.7ns   1.311V     740.6mV    1.627V
169ns     1.325V     878.8mV    1.628V
398.8ns   1.33V      980.7mV    1.628V
[Falling Waveform]
R_fixture= 50.000000
V_fixture= 1.800000
V_fixture_min= 1.600000
V_fixture_max= 2.000000
|time   V(typ)   V(min)   V(max)
0s        1.8V       1.6V       2V
16.82ns   1.8V       1.6V       1.929V
21.62ns   1.797V     1.6V       1.684V
35.24ns   1.624V     1.597V     576.1mV
52.85ns   1V         1.544V     351.2mV
61.66ns   705.9mV    1.488V     325.7mV
72.87ns   568.5mV    1.389V     309.1mV
115.3ns   448.5mV    927.6mV    290.6mV
150.6ns   426.2mV    775.5mV    288.3mV
398.8ns   414.4mV    657.5mV    287.6mV
[Falling Waveform]
R_fixture= 50.000000
V_fixture= 0.0
V_fixture_min= 0.0
V_fixture_max= 0.0
|time   V(typ)   V(min)   V(max)
0s        1.33V      980.7mV    1.628V
1.842ns   1.331V     980.7mV    1.538V
2.162ns   1.335V     980.7mV    1.339V
2.723ns   1.198V     980.5mV    720.7mV
3.403ns   781mV      987.4mV    176.8mV
3.924ns   428.4mV    908.3mV    26.93mV
5.165ns   31.93mV    481.2mV    2.696mV
6.166ns   3.489mV    213.2mV    1.564mV
7.728ns   907.9uV    22.53mV    1.342mV
19.94ns   425uV      507.6uV    388.2uV
